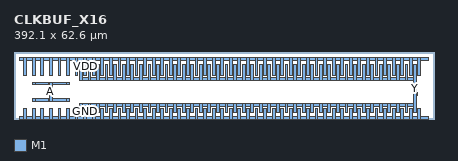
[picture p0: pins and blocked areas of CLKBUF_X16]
MACRO CLKBUF_X16
  CLASS CORE ;
  ORIGIN 0 0 ;
  SIZE 392.100 BY 62.600 ;
  SYMMETRY X Y ;
  SITE TR1um_site ;
  PIN A
    DIRECTION INPUT ;
    USE SIGNAL ;
    PORT
      LAYER M1 ;
        RECT 17.100 16.400 19.700 19.000 ;
      LAYER M1 ;
        RECT 17.100 31.800 19.700 34.400 ;
      LAYER M1 ;
        RECT 19.700 16.700 32.100 18.700 ;
      LAYER M1 ;
        RECT 19.700 32.100 32.100 34.100 ;
      LAYER M1 ;
        RECT 32.100 16.700 32.700 18.700 ;
      LAYER M1 ;
        RECT 32.100 21.600 32.700 25.000 ;
      LAYER M1 ;
        RECT 32.100 32.100 32.700 34.100 ;
      LAYER M1 ;
        RECT 32.700 16.700 33.100 34.100 ;
      LAYER M1 ;
        RECT 33.100 16.400 35.700 34.400 ;
      LAYER M1 ;
        RECT 35.700 16.700 36.100 34.100 ;
      LAYER M1 ;
        RECT 36.100 16.700 49.100 18.700 ;
      LAYER M1 ;
        RECT 36.100 32.100 49.100 34.100 ;
      LAYER M1 ;
        RECT 49.100 16.400 51.700 19.000 ;
      LAYER M1 ;
        RECT 49.100 31.800 51.700 34.400 ;
    END
  END A
  PIN Y
    DIRECTION OUTPUT ;
    USE SIGNAL ;
    PORT
      LAYER M1 ;
        RECT 61.100 6.400 63.700 14.400 ;
      LAYER M1 ;
        RECT 61.100 36.400 63.700 51.200 ;
      LAYER M1 ;
        RECT 63.700 11.800 69.100 14.400 ;
      LAYER M1 ;
        RECT 63.700 36.400 69.100 39.000 ;
      LAYER M1 ;
        RECT 69.100 6.400 71.700 14.400 ;
      LAYER M1 ;
        RECT 69.100 36.400 71.700 51.200 ;
      LAYER M1 ;
        RECT 71.700 11.800 77.100 14.400 ;
      LAYER M1 ;
        RECT 71.700 36.400 77.100 39.000 ;
      LAYER M1 ;
        RECT 77.100 6.400 79.700 14.400 ;
      LAYER M1 ;
        RECT 77.100 36.400 79.700 51.200 ;
      LAYER M1 ;
        RECT 79.700 11.800 85.100 14.400 ;
      LAYER M1 ;
        RECT 79.700 36.400 85.100 39.000 ;
      LAYER M1 ;
        RECT 85.100 6.400 87.700 14.400 ;
      LAYER M1 ;
        RECT 85.100 36.400 87.700 51.200 ;
      LAYER M1 ;
        RECT 87.700 11.800 93.100 14.400 ;
      LAYER M1 ;
        RECT 87.700 36.400 93.100 39.000 ;
      LAYER M1 ;
        RECT 93.100 6.400 95.700 14.400 ;
      LAYER M1 ;
        RECT 93.100 36.400 95.700 51.200 ;
      LAYER M1 ;
        RECT 95.700 11.800 101.100 14.400 ;
      LAYER M1 ;
        RECT 95.700 36.400 101.100 39.000 ;
      LAYER M1 ;
        RECT 101.100 6.400 103.700 14.400 ;
      LAYER M1 ;
        RECT 101.100 36.400 103.700 51.200 ;
      LAYER M1 ;
        RECT 103.700 11.800 109.100 14.400 ;
      LAYER M1 ;
        RECT 103.700 36.400 109.100 39.000 ;
      LAYER M1 ;
        RECT 109.100 6.400 111.700 14.400 ;
      LAYER M1 ;
        RECT 109.100 36.400 111.700 51.200 ;
      LAYER M1 ;
        RECT 111.700 11.800 117.100 14.400 ;
      LAYER M1 ;
        RECT 111.700 36.400 117.100 39.000 ;
      LAYER M1 ;
        RECT 117.100 6.400 119.700 14.400 ;
      LAYER M1 ;
        RECT 117.100 36.400 119.700 51.200 ;
      LAYER M1 ;
        RECT 119.700 11.800 125.100 14.400 ;
      LAYER M1 ;
        RECT 119.700 36.400 125.100 39.000 ;
      LAYER M1 ;
        RECT 125.100 6.400 127.700 14.400 ;
      LAYER M1 ;
        RECT 125.100 36.400 127.700 51.200 ;
      LAYER M1 ;
        RECT 127.700 11.800 133.100 14.400 ;
      LAYER M1 ;
        RECT 127.700 36.400 133.100 39.000 ;
      LAYER M1 ;
        RECT 133.100 6.400 135.700 14.400 ;
      LAYER M1 ;
        RECT 133.100 36.400 135.700 51.200 ;
      LAYER M1 ;
        RECT 135.700 11.800 141.100 14.400 ;
      LAYER M1 ;
        RECT 135.700 36.400 141.100 39.000 ;
      LAYER M1 ;
        RECT 141.100 6.400 143.700 14.400 ;
      LAYER M1 ;
        RECT 141.100 36.400 143.700 51.200 ;
      LAYER M1 ;
        RECT 143.700 11.800 149.100 14.400 ;
      LAYER M1 ;
        RECT 143.700 36.400 149.100 39.000 ;
      LAYER M1 ;
        RECT 149.100 6.400 151.700 14.400 ;
      LAYER M1 ;
        RECT 149.100 36.400 151.700 51.200 ;
      LAYER M1 ;
        RECT 151.700 11.800 157.100 14.400 ;
      LAYER M1 ;
        RECT 151.700 36.400 157.100 39.000 ;
      LAYER M1 ;
        RECT 157.100 6.400 159.700 14.400 ;
      LAYER M1 ;
        RECT 157.100 36.400 159.700 51.200 ;
      LAYER M1 ;
        RECT 159.700 11.800 165.100 14.400 ;
      LAYER M1 ;
        RECT 159.700 36.400 165.100 39.000 ;
      LAYER M1 ;
        RECT 165.100 6.400 167.700 14.400 ;
      LAYER M1 ;
        RECT 165.100 36.400 167.700 51.200 ;
      LAYER M1 ;
        RECT 167.700 11.800 173.100 14.400 ;
      LAYER M1 ;
        RECT 167.700 36.400 173.100 39.000 ;
      LAYER M1 ;
        RECT 173.100 6.400 175.700 14.400 ;
      LAYER M1 ;
        RECT 173.100 36.400 175.700 51.200 ;
      LAYER M1 ;
        RECT 175.700 11.800 181.100 14.400 ;
      LAYER M1 ;
        RECT 175.700 36.400 181.100 39.000 ;
      LAYER M1 ;
        RECT 181.100 6.400 183.700 14.400 ;
      LAYER M1 ;
        RECT 181.100 36.400 183.700 51.200 ;
      LAYER M1 ;
        RECT 183.700 11.800 189.100 14.400 ;
      LAYER M1 ;
        RECT 183.700 36.400 189.100 39.000 ;
      LAYER M1 ;
        RECT 189.100 6.400 191.700 14.400 ;
      LAYER M1 ;
        RECT 189.100 36.400 191.700 51.200 ;
      LAYER M1 ;
        RECT 191.700 11.800 197.100 14.400 ;
      LAYER M1 ;
        RECT 191.700 36.400 197.100 39.000 ;
      LAYER M1 ;
        RECT 197.100 6.400 199.700 14.400 ;
      LAYER M1 ;
        RECT 197.100 36.400 199.700 51.200 ;
      LAYER M1 ;
        RECT 199.700 11.800 205.100 14.400 ;
      LAYER M1 ;
        RECT 199.700 36.400 205.100 39.000 ;
      LAYER M1 ;
        RECT 205.100 6.400 207.700 14.400 ;
      LAYER M1 ;
        RECT 205.100 36.400 207.700 51.200 ;
      LAYER M1 ;
        RECT 207.700 11.800 213.100 14.400 ;
      LAYER M1 ;
        RECT 207.700 36.400 213.100 39.000 ;
      LAYER M1 ;
        RECT 213.100 6.400 215.700 14.400 ;
      LAYER M1 ;
        RECT 213.100 36.400 215.700 51.200 ;
      LAYER M1 ;
        RECT 215.700 11.800 221.100 14.400 ;
      LAYER M1 ;
        RECT 215.700 36.400 221.100 39.000 ;
      LAYER M1 ;
        RECT 221.100 6.400 223.700 14.400 ;
      LAYER M1 ;
        RECT 221.100 36.400 223.700 51.200 ;
      LAYER M1 ;
        RECT 223.700 11.800 229.100 14.400 ;
      LAYER M1 ;
        RECT 223.700 36.400 229.100 39.000 ;
      LAYER M1 ;
        RECT 229.100 6.400 231.700 14.400 ;
      LAYER M1 ;
        RECT 229.100 36.400 231.700 51.200 ;
      LAYER M1 ;
        RECT 231.700 11.800 237.100 14.400 ;
      LAYER M1 ;
        RECT 231.700 36.400 237.100 39.000 ;
      LAYER M1 ;
        RECT 237.100 6.400 239.700 14.400 ;
      LAYER M1 ;
        RECT 237.100 36.400 239.700 51.200 ;
      LAYER M1 ;
        RECT 239.700 11.800 245.100 14.400 ;
      LAYER M1 ;
        RECT 239.700 36.400 245.100 39.000 ;
      LAYER M1 ;
        RECT 245.100 6.400 247.700 14.400 ;
      LAYER M1 ;
        RECT 245.100 36.400 247.700 51.200 ;
      LAYER M1 ;
        RECT 247.700 11.800 253.100 14.400 ;
      LAYER M1 ;
        RECT 247.700 36.400 253.100 39.000 ;
      LAYER M1 ;
        RECT 253.100 6.400 255.700 14.400 ;
      LAYER M1 ;
        RECT 253.100 36.400 255.700 51.200 ;
      LAYER M1 ;
        RECT 255.700 11.800 261.100 14.400 ;
      LAYER M1 ;
        RECT 255.700 36.400 261.100 39.000 ;
      LAYER M1 ;
        RECT 261.100 6.400 263.700 14.400 ;
      LAYER M1 ;
        RECT 261.100 36.400 263.700 51.200 ;
      LAYER M1 ;
        RECT 263.700 11.800 269.100 14.400 ;
      LAYER M1 ;
        RECT 263.700 36.400 269.100 39.000 ;
      LAYER M1 ;
        RECT 269.100 6.400 271.700 14.400 ;
      LAYER M1 ;
        RECT 269.100 36.400 271.700 51.200 ;
      LAYER M1 ;
        RECT 271.700 11.800 277.100 14.400 ;
      LAYER M1 ;
        RECT 271.700 36.400 277.100 39.000 ;
      LAYER M1 ;
        RECT 277.100 6.400 279.700 14.400 ;
      LAYER M1 ;
        RECT 277.100 36.400 279.700 51.200 ;
      LAYER M1 ;
        RECT 279.700 11.800 285.100 14.400 ;
      LAYER M1 ;
        RECT 279.700 36.400 285.100 39.000 ;
      LAYER M1 ;
        RECT 285.100 6.400 287.700 14.400 ;
      LAYER M1 ;
        RECT 285.100 36.400 287.700 51.200 ;
      LAYER M1 ;
        RECT 287.700 11.800 293.100 14.400 ;
      LAYER M1 ;
        RECT 287.700 36.400 293.100 39.000 ;
      LAYER M1 ;
        RECT 293.100 6.400 295.700 14.400 ;
      LAYER M1 ;
        RECT 293.100 36.400 295.700 51.200 ;
      LAYER M1 ;
        RECT 295.700 11.800 301.100 14.400 ;
      LAYER M1 ;
        RECT 295.700 36.400 301.100 39.000 ;
      LAYER M1 ;
        RECT 301.100 6.400 303.700 14.400 ;
      LAYER M1 ;
        RECT 301.100 36.400 303.700 51.200 ;
      LAYER M1 ;
        RECT 303.700 11.800 309.100 14.400 ;
      LAYER M1 ;
        RECT 303.700 36.400 309.100 39.000 ;
      LAYER M1 ;
        RECT 309.100 6.400 311.700 14.400 ;
      LAYER M1 ;
        RECT 309.100 36.400 311.700 51.200 ;
      LAYER M1 ;
        RECT 311.700 11.800 317.100 14.400 ;
      LAYER M1 ;
        RECT 311.700 36.400 317.100 39.000 ;
      LAYER M1 ;
        RECT 317.100 6.400 319.700 14.400 ;
      LAYER M1 ;
        RECT 317.100 36.400 319.700 51.200 ;
      LAYER M1 ;
        RECT 319.700 11.800 325.100 14.400 ;
      LAYER M1 ;
        RECT 319.700 36.400 325.100 39.000 ;
      LAYER M1 ;
        RECT 325.100 6.400 327.700 14.400 ;
      LAYER M1 ;
        RECT 325.100 36.400 327.700 51.200 ;
      LAYER M1 ;
        RECT 327.700 11.800 333.100 14.400 ;
      LAYER M1 ;
        RECT 327.700 36.400 333.100 39.000 ;
      LAYER M1 ;
        RECT 333.100 6.400 335.700 14.400 ;
      LAYER M1 ;
        RECT 333.100 36.400 335.700 51.200 ;
      LAYER M1 ;
        RECT 335.700 11.800 341.100 14.400 ;
      LAYER M1 ;
        RECT 335.700 36.400 341.100 39.000 ;
      LAYER M1 ;
        RECT 341.100 6.400 343.700 14.400 ;
      LAYER M1 ;
        RECT 341.100 36.400 343.700 51.200 ;
      LAYER M1 ;
        RECT 343.700 11.800 349.100 14.400 ;
      LAYER M1 ;
        RECT 343.700 36.400 349.100 39.000 ;
      LAYER M1 ;
        RECT 349.100 6.400 351.700 14.400 ;
      LAYER M1 ;
        RECT 349.100 36.400 351.700 51.200 ;
      LAYER M1 ;
        RECT 351.700 11.800 357.100 14.400 ;
      LAYER M1 ;
        RECT 351.700 36.400 357.100 39.000 ;
      LAYER M1 ;
        RECT 357.100 6.400 359.700 14.400 ;
      LAYER M1 ;
        RECT 357.100 36.400 359.700 51.200 ;
      LAYER M1 ;
        RECT 359.700 11.800 365.100 14.400 ;
      LAYER M1 ;
        RECT 359.700 36.400 365.100 39.000 ;
      LAYER M1 ;
        RECT 365.100 6.400 367.700 14.400 ;
      LAYER M1 ;
        RECT 365.100 36.400 367.700 51.200 ;
      LAYER M1 ;
        RECT 367.700 11.800 373.100 14.400 ;
      LAYER M1 ;
        RECT 367.700 36.400 373.100 39.000 ;
      LAYER M1 ;
        RECT 373.100 6.400 375.700 51.200 ;
      LAYER M1 ;
        RECT 375.700 21.600 376.500 25.000 ;
    END
  END Y
  PIN VDD
    DIRECTION INOUT ;
    USE POWER ;
    PORT
      LAYER M1 ;
        RECT 5.000 55.000 9.100 57.600 ;
      LAYER M1 ;
        RECT 9.100 41.000 11.700 57.600 ;
      LAYER M1 ;
        RECT 11.700 55.000 17.100 57.600 ;
      LAYER M1 ;
        RECT 17.100 41.000 19.700 57.600 ;
      LAYER M1 ;
        RECT 19.700 55.000 25.100 57.600 ;
      LAYER M1 ;
        RECT 25.100 41.000 27.700 57.600 ;
      LAYER M1 ;
        RECT 27.700 55.000 33.100 57.600 ;
      LAYER M1 ;
        RECT 33.100 41.000 35.700 57.600 ;
      LAYER M1 ;
        RECT 35.700 55.000 41.100 57.600 ;
      LAYER M1 ;
        RECT 41.100 41.000 43.700 57.600 ;
      LAYER M1 ;
        RECT 43.700 55.000 49.100 57.600 ;
      LAYER M1 ;
        RECT 49.100 41.000 51.700 57.600 ;
      LAYER M1 ;
        RECT 51.700 55.000 57.100 57.600 ;
      LAYER M1 ;
        RECT 57.100 41.000 59.700 57.600 ;
      LAYER M1 ;
        RECT 59.700 55.000 65.100 57.600 ;
      LAYER M1 ;
        RECT 65.100 41.000 67.700 57.600 ;
      LAYER M1 ;
        RECT 67.700 55.000 73.100 57.600 ;
      LAYER M1 ;
        RECT 73.100 41.000 75.700 57.600 ;
      LAYER M1 ;
        RECT 75.700 55.000 81.100 57.600 ;
      LAYER M1 ;
        RECT 81.100 41.000 83.700 57.600 ;
      LAYER M1 ;
        RECT 83.700 55.000 89.100 57.600 ;
      LAYER M1 ;
        RECT 89.100 41.000 91.700 57.600 ;
      LAYER M1 ;
        RECT 91.700 55.000 97.100 57.600 ;
      LAYER M1 ;
        RECT 97.100 41.000 99.700 57.600 ;
      LAYER M1 ;
        RECT 99.700 55.000 105.100 57.600 ;
      LAYER M1 ;
        RECT 105.100 41.000 107.700 57.600 ;
      LAYER M1 ;
        RECT 107.700 55.000 113.100 57.600 ;
      LAYER M1 ;
        RECT 113.100 41.000 115.700 57.600 ;
      LAYER M1 ;
        RECT 115.700 55.000 121.100 57.600 ;
      LAYER M1 ;
        RECT 121.100 41.000 123.700 57.600 ;
      LAYER M1 ;
        RECT 123.700 55.000 129.100 57.600 ;
      LAYER M1 ;
        RECT 129.100 41.000 131.700 57.600 ;
      LAYER M1 ;
        RECT 131.700 55.000 137.100 57.600 ;
      LAYER M1 ;
        RECT 137.100 41.000 139.700 57.600 ;
      LAYER M1 ;
        RECT 139.700 55.000 145.100 57.600 ;
      LAYER M1 ;
        RECT 145.100 41.000 147.700 57.600 ;
      LAYER M1 ;
        RECT 147.700 55.000 153.100 57.600 ;
      LAYER M1 ;
        RECT 153.100 41.000 155.700 57.600 ;
      LAYER M1 ;
        RECT 155.700 55.000 161.100 57.600 ;
      LAYER M1 ;
        RECT 161.100 41.000 163.700 57.600 ;
      LAYER M1 ;
        RECT 163.700 55.000 169.100 57.600 ;
      LAYER M1 ;
        RECT 169.100 41.000 171.700 57.600 ;
      LAYER M1 ;
        RECT 171.700 55.000 177.100 57.600 ;
      LAYER M1 ;
        RECT 177.100 41.000 179.700 57.600 ;
      LAYER M1 ;
        RECT 179.700 55.000 185.100 57.600 ;
      LAYER M1 ;
        RECT 185.100 41.000 187.700 57.600 ;
      LAYER M1 ;
        RECT 187.700 55.000 193.100 57.600 ;
      LAYER M1 ;
        RECT 193.100 41.000 195.700 57.600 ;
      LAYER M1 ;
        RECT 195.700 55.000 201.100 57.600 ;
      LAYER M1 ;
        RECT 201.100 41.000 203.700 57.600 ;
      LAYER M1 ;
        RECT 203.700 55.000 209.100 57.600 ;
      LAYER M1 ;
        RECT 209.100 41.000 211.700 57.600 ;
      LAYER M1 ;
        RECT 211.700 55.000 217.100 57.600 ;
      LAYER M1 ;
        RECT 217.100 41.000 219.700 57.600 ;
      LAYER M1 ;
        RECT 219.700 55.000 225.100 57.600 ;
      LAYER M1 ;
        RECT 225.100 41.000 227.700 57.600 ;
      LAYER M1 ;
        RECT 227.700 55.000 233.100 57.600 ;
      LAYER M1 ;
        RECT 233.100 41.000 235.700 57.600 ;
      LAYER M1 ;
        RECT 235.700 55.000 241.100 57.600 ;
      LAYER M1 ;
        RECT 241.100 41.000 243.700 57.600 ;
      LAYER M1 ;
        RECT 243.700 55.000 249.100 57.600 ;
      LAYER M1 ;
        RECT 249.100 41.000 251.700 57.600 ;
      LAYER M1 ;
        RECT 251.700 55.000 257.100 57.600 ;
      LAYER M1 ;
        RECT 257.100 41.000 259.700 57.600 ;
      LAYER M1 ;
        RECT 259.700 55.000 265.100 57.600 ;
      LAYER M1 ;
        RECT 265.100 41.000 267.700 57.600 ;
      LAYER M1 ;
        RECT 267.700 55.000 273.100 57.600 ;
      LAYER M1 ;
        RECT 273.100 41.000 275.700 57.600 ;
      LAYER M1 ;
        RECT 275.700 55.000 281.100 57.600 ;
      LAYER M1 ;
        RECT 281.100 41.000 283.700 57.600 ;
      LAYER M1 ;
        RECT 283.700 55.000 289.100 57.600 ;
      LAYER M1 ;
        RECT 289.100 41.000 291.700 57.600 ;
      LAYER M1 ;
        RECT 291.700 55.000 297.100 57.600 ;
      LAYER M1 ;
        RECT 297.100 41.000 299.700 57.600 ;
      LAYER M1 ;
        RECT 299.700 55.000 305.100 57.600 ;
      LAYER M1 ;
        RECT 305.100 41.000 307.700 57.600 ;
      LAYER M1 ;
        RECT 307.700 55.000 313.100 57.600 ;
      LAYER M1 ;
        RECT 313.100 41.000 315.700 57.600 ;
      LAYER M1 ;
        RECT 315.700 55.000 321.100 57.600 ;
      LAYER M1 ;
        RECT 321.100 41.000 323.700 57.600 ;
      LAYER M1 ;
        RECT 323.700 55.000 329.100 57.600 ;
      LAYER M1 ;
        RECT 329.100 41.000 331.700 57.600 ;
      LAYER M1 ;
        RECT 331.700 55.000 337.100 57.600 ;
      LAYER M1 ;
        RECT 337.100 41.000 339.700 57.600 ;
      LAYER M1 ;
        RECT 339.700 55.000 345.100 57.600 ;
      LAYER M1 ;
        RECT 345.100 41.000 347.700 57.600 ;
      LAYER M1 ;
        RECT 347.700 55.000 353.100 57.600 ;
      LAYER M1 ;
        RECT 353.100 41.000 355.700 57.600 ;
      LAYER M1 ;
        RECT 355.700 55.000 361.100 57.600 ;
      LAYER M1 ;
        RECT 361.100 41.000 363.700 57.600 ;
      LAYER M1 ;
        RECT 363.700 55.000 369.100 57.600 ;
      LAYER M1 ;
        RECT 369.100 41.000 371.700 57.600 ;
      LAYER M1 ;
        RECT 371.700 55.000 377.100 57.600 ;
      LAYER M1 ;
        RECT 377.100 41.000 379.700 57.600 ;
      LAYER M1 ;
        RECT 379.700 55.000 387.100 57.600 ;
    END
  END VDD
  PIN GND
    DIRECTION INOUT ;
    USE GROUND ;
    PORT
      LAYER M1 ;
        RECT 5.000 0.000 9.100 2.600 ;
      LAYER M1 ;
        RECT 9.100 0.000 11.700 9.800 ;
      LAYER M1 ;
        RECT 11.700 0.000 17.100 2.600 ;
      LAYER M1 ;
        RECT 17.100 0.000 19.700 9.800 ;
      LAYER M1 ;
        RECT 19.700 0.000 25.100 2.600 ;
      LAYER M1 ;
        RECT 25.100 0.000 27.700 9.800 ;
      LAYER M1 ;
        RECT 27.700 0.000 33.100 2.600 ;
      LAYER M1 ;
        RECT 33.100 0.000 35.700 9.800 ;
      LAYER M1 ;
        RECT 35.700 0.000 41.100 2.600 ;
      LAYER M1 ;
        RECT 41.100 0.000 43.700 9.800 ;
      LAYER M1 ;
        RECT 43.700 0.000 49.100 2.600 ;
      LAYER M1 ;
        RECT 49.100 0.000 51.700 9.800 ;
      LAYER M1 ;
        RECT 51.700 0.000 57.100 2.600 ;
      LAYER M1 ;
        RECT 57.100 0.000 59.700 9.800 ;
      LAYER M1 ;
        RECT 59.700 0.000 65.100 2.600 ;
      LAYER M1 ;
        RECT 65.100 0.000 67.700 9.800 ;
      LAYER M1 ;
        RECT 67.700 0.000 73.100 2.600 ;
      LAYER M1 ;
        RECT 73.100 0.000 75.700 9.800 ;
      LAYER M1 ;
        RECT 75.700 0.000 81.100 2.600 ;
      LAYER M1 ;
        RECT 81.100 0.000 83.700 9.800 ;
      LAYER M1 ;
        RECT 83.700 0.000 89.100 2.600 ;
      LAYER M1 ;
        RECT 89.100 0.000 91.700 9.800 ;
      LAYER M1 ;
        RECT 91.700 0.000 97.100 2.600 ;
      LAYER M1 ;
        RECT 97.100 0.000 99.700 9.800 ;
      LAYER M1 ;
        RECT 99.700 0.000 105.100 2.600 ;
      LAYER M1 ;
        RECT 105.100 0.000 107.700 9.800 ;
      LAYER M1 ;
        RECT 107.700 0.000 113.100 2.600 ;
      LAYER M1 ;
        RECT 113.100 0.000 115.700 9.800 ;
      LAYER M1 ;
        RECT 115.700 0.000 121.100 2.600 ;
      LAYER M1 ;
        RECT 121.100 0.000 123.700 9.800 ;
      LAYER M1 ;
        RECT 123.700 0.000 129.100 2.600 ;
      LAYER M1 ;
        RECT 129.100 0.000 131.700 9.800 ;
      LAYER M1 ;
        RECT 131.700 0.000 137.100 2.600 ;
      LAYER M1 ;
        RECT 137.100 0.000 139.700 9.800 ;
      LAYER M1 ;
        RECT 139.700 0.000 145.100 2.600 ;
      LAYER M1 ;
        RECT 145.100 0.000 147.700 9.800 ;
      LAYER M1 ;
        RECT 147.700 0.000 153.100 2.600 ;
      LAYER M1 ;
        RECT 153.100 0.000 155.700 9.800 ;
      LAYER M1 ;
        RECT 155.700 0.000 161.100 2.600 ;
      LAYER M1 ;
        RECT 161.100 0.000 163.700 9.800 ;
      LAYER M1 ;
        RECT 163.700 0.000 169.100 2.600 ;
      LAYER M1 ;
        RECT 169.100 0.000 171.700 9.800 ;
      LAYER M1 ;
        RECT 171.700 0.000 177.100 2.600 ;
      LAYER M1 ;
        RECT 177.100 0.000 179.700 9.800 ;
      LAYER M1 ;
        RECT 179.700 0.000 185.100 2.600 ;
      LAYER M1 ;
        RECT 185.100 0.000 187.700 9.800 ;
      LAYER M1 ;
        RECT 187.700 0.000 193.100 2.600 ;
      LAYER M1 ;
        RECT 193.100 0.000 195.700 9.800 ;
      LAYER M1 ;
        RECT 195.700 0.000 201.100 2.600 ;
      LAYER M1 ;
        RECT 201.100 0.000 203.700 9.800 ;
      LAYER M1 ;
        RECT 203.700 0.000 209.100 2.600 ;
      LAYER M1 ;
        RECT 209.100 0.000 211.700 9.800 ;
      LAYER M1 ;
        RECT 211.700 0.000 217.100 2.600 ;
      LAYER M1 ;
        RECT 217.100 0.000 219.700 9.800 ;
      LAYER M1 ;
        RECT 219.700 0.000 225.100 2.600 ;
      LAYER M1 ;
        RECT 225.100 0.000 227.700 9.800 ;
      LAYER M1 ;
        RECT 227.700 0.000 233.100 2.600 ;
      LAYER M1 ;
        RECT 233.100 0.000 235.700 9.800 ;
      LAYER M1 ;
        RECT 235.700 0.000 241.100 2.600 ;
      LAYER M1 ;
        RECT 241.100 0.000 243.700 9.800 ;
      LAYER M1 ;
        RECT 243.700 0.000 249.100 2.600 ;
      LAYER M1 ;
        RECT 249.100 0.000 251.700 9.800 ;
      LAYER M1 ;
        RECT 251.700 0.000 257.100 2.600 ;
      LAYER M1 ;
        RECT 257.100 0.000 259.700 9.800 ;
      LAYER M1 ;
        RECT 259.700 0.000 265.100 2.600 ;
      LAYER M1 ;
        RECT 265.100 0.000 267.700 9.800 ;
      LAYER M1 ;
        RECT 267.700 0.000 273.100 2.600 ;
      LAYER M1 ;
        RECT 273.100 0.000 275.700 9.800 ;
      LAYER M1 ;
        RECT 275.700 0.000 281.100 2.600 ;
      LAYER M1 ;
        RECT 281.100 0.000 283.700 9.800 ;
      LAYER M1 ;
        RECT 283.700 0.000 289.100 2.600 ;
      LAYER M1 ;
        RECT 289.100 0.000 291.700 9.800 ;
      LAYER M1 ;
        RECT 291.700 0.000 297.100 2.600 ;
      LAYER M1 ;
        RECT 297.100 0.000 299.700 9.800 ;
      LAYER M1 ;
        RECT 299.700 0.000 305.100 2.600 ;
      LAYER M1 ;
        RECT 305.100 0.000 307.700 9.800 ;
      LAYER M1 ;
        RECT 307.700 0.000 313.100 2.600 ;
      LAYER M1 ;
        RECT 313.100 0.000 315.700 9.800 ;
      LAYER M1 ;
        RECT 315.700 0.000 321.100 2.600 ;
      LAYER M1 ;
        RECT 321.100 0.000 323.700 9.800 ;
      LAYER M1 ;
        RECT 323.700 0.000 329.100 2.600 ;
      LAYER M1 ;
        RECT 329.100 0.000 331.700 9.800 ;
      LAYER M1 ;
        RECT 331.700 0.000 337.100 2.600 ;
      LAYER M1 ;
        RECT 337.100 0.000 339.700 9.800 ;
      LAYER M1 ;
        RECT 339.700 0.000 345.100 2.600 ;
      LAYER M1 ;
        RECT 345.100 0.000 347.700 9.800 ;
      LAYER M1 ;
        RECT 347.700 0.000 353.100 2.600 ;
      LAYER M1 ;
        RECT 353.100 0.000 355.700 9.800 ;
      LAYER M1 ;
        RECT 355.700 0.000 361.100 2.600 ;
      LAYER M1 ;
        RECT 361.100 0.000 363.700 9.800 ;
      LAYER M1 ;
        RECT 363.700 0.000 369.100 2.600 ;
      LAYER M1 ;
        RECT 369.100 0.000 371.700 9.800 ;
      LAYER M1 ;
        RECT 371.700 0.000 377.100 2.600 ;
      LAYER M1 ;
        RECT 377.100 0.000 379.700 9.800 ;
      LAYER M1 ;
        RECT 379.700 0.000 387.100 2.600 ;
    END
  END GND
END CLKBUF_X16
